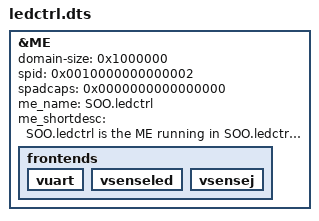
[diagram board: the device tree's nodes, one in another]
/*
 * Copyright (C) 2016-2018 Daniel Rossier <daniel.rossier@soo.tech>
 *
 * This program is free software; you can redistribute it and/or modify
 * it under the terms of the GNU General Public License version 2 as
 * published by the Free Software Foundation.
 *
 * This program is distributed in the hope that it will be useful,
 * but WITHOUT ANY WARRANTY; without even the implied warranty of
 * MERCHANTABILITY or FITNESS FOR A PARTICULAR PURPOSE.  See the
 * GNU General Public License for more details.
 *
 * You should have received a copy of the GNU General Public License
 * along with this program; if not, write to the Free Software
 * Foundation, Inc., 51 Franklin St, Fifth Floor, Boston, MA  02110-1301  USA
 *
 */

/dts-v1/;

#include "soo.dtsi"

&ME {
	/* 16 MB should be enough for major cases. */
	domain-size = <0x1000000>;
	
	/* SPID on 64-bit encoding */
	spid = /bits/ 64 <0x0010000000000002>;
	
	/* SPAD capabilities on 64-bit encoding */
	spadcaps = /bits/ 64 <0x0000000000000000>;
	
	/* Name of this ME */
	me_name = "SOO.ledctrl";
	
	/* Short description */
	me_shortdesc =
			
"SOO.ledctrl is the ME running in SOO.ledctrl smart object which is \
a Raspberry Pi 4 enhanced with the Sense HAT extension. This ME \
basically uses the led matrix and joystick.";

	frontends {
	
		/* Enabling the console */
		vuart {
			status = "ok";
		};
		
		vsenseled {
			status = "ok";
		};
		
		vsensej {
			status = "ok";
		};
		
	};
};
			
